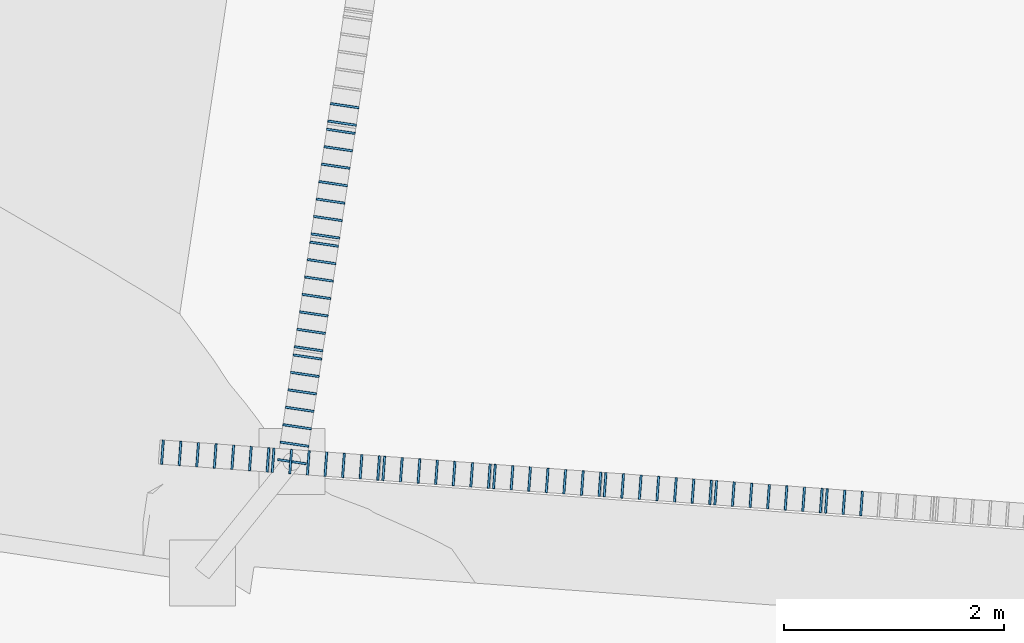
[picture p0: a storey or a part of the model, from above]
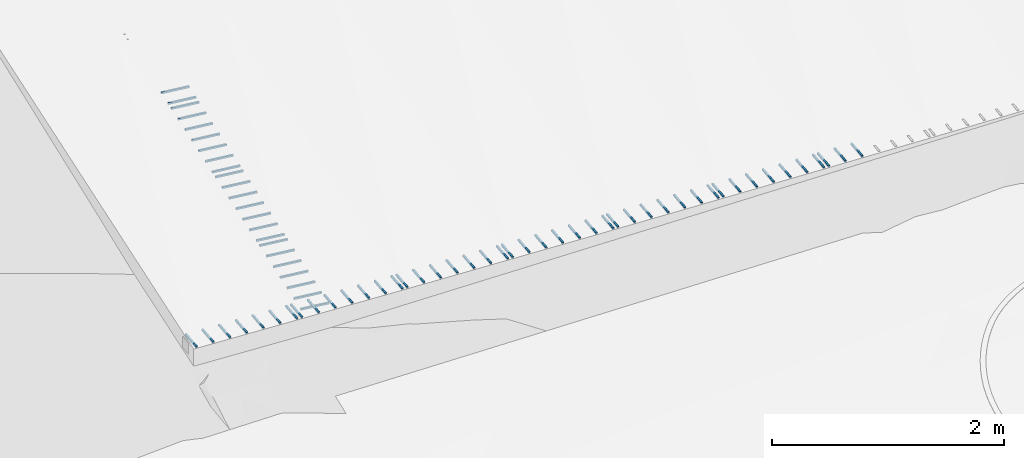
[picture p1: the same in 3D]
Properties of the parts of a building model (IFC4), part 1 of 4

# File
Description: ViewDefinition [CoordinationView]
File name: Casa_Sobreposta_Implantada.ifc
Time: 2026-10-02T14:30:32
Written by: IfcOpenShell 0.8.0
Made in: IfcOpenShell 0.8.0

# IfcProject, Casa / Lares · R08 · Estufa
Pset_CasaModel - Design: R08 / estufa / lower hybrid podium and ground-supported parking; ReferenceFile: 260617_CasaDFL_Estrutura_Terreno.ifc; ModelStatus: DESIGN_STUDY; North: Survey grid +Y; Ramp: No exterior pedestrian ramp or vehicular bridge; EngineeringStatus: Member sizes, foundations, connections, bracing and environmental performance not verified; GroundFFL_m: 14.65; AreaLimit_m2: 250; CountedGeometricArea_m2: 181.073; GreenhouseExcludedByUser: yes; UpperFinishedFloor_m: 17.89; BalconiesExcludedByClient: yes; CoveredGroundBalcony_m2: 56.7788; PlanningComplianceEstablished: no; AreaBasis: Client-confirmed 250 m2 allowance: parking, cistern, balconies and open greenhouse excluded; enclosed upper rooms and stair enclosures count. Any storage would count. Geometric study, no independent PDM verification.

# IfcSite, Lares · Rua das Mercês · artigo 4771
Pset_SurveySource - File: GN_09.26_213 Lares.dwg; SHA256: 0bca0a0751148bad1398f92d81b795428f94a57fea5e37dec0e125cea70402a1; Area_m2: 1636.5; BoundaryHandle: 31B; CoordinateReference: PT-TM06 / ETRS89; TerrainStatus: Proposed grading; original survey in separate IFC

# IfcBuilding, Casa Sobreposta
Pset_CasaFloorAssembly - UpperFFL_m: 3.24; JoistUnderside_m: 2.968; JoistDepth_m: 0.24; OSB_m: 0.02; Membrane_m: 0.002; ProtectiveFinish_m: 0.01; Basis: TJI240 + OSB20 from reference; greenhouse waterproofing/finish assumed; imposed loads unverified
Pset_CasaPlacement - GroundFloorSurveyLevel_m: 14.65; UpperFloor: yes; MoveEast_m: 3; MoveSouth_m: 0.5; RotationFromGridEast_deg: -8.5; BoundarySetbackRequired_m: 3; RuleBasis: User project constraint
Pset_CasaRevision08 - Variant: estufa; HybridPodium: yes; ParkingGroundSupported: yes; GroundFFL_m: 14.65; TerraceFFL_m: 14.61; VehicularBridgeLength_m: 0; AccessGabions: no; Cut_m3: 106.804; Fill_m3: 2.37597; EarthworkExclusions: Topsoil, foundation/service trenches, soil replacement, construction working space and bulking; CoveredGroundBalconyClassification: EXCLUDED_BY_CLIENT; WindCapacityVerified: no

# IfcBuildingStorey (3)
In: Casa Sobreposta
Name | Elevation (m)
00 · Habitação e estacionamento | 14.65
01 · Jardim de inverno | 17.89
-01 · Cisterna sob o terraço | 12.05

# IfcSpace (18)
Pset_CasaProvenance - DesignSource: Casa Sobreposta / configuration.json; ReferenceFile: 260617_CasaDFL_Estrutura_Terreno.ifc; ConstructionBasis: DESIGN_ASSUMPTION; Note: Functional zone from configurator; overlaps with partition footprints removed on ground floor. Not certified usable floor area.
Name | In | PredefinedType | NetFloorArea (m2)
Sala | 00 · Habitação e estacionamento | INTERNAL | 31.359
Cozinha | 00 · Habitação e estacionamento | INTERNAL | 9.94248
Banho | 00 · Habitação e estacionamento | INTERNAL | 7.19804
WC | 00 · Habitação e estacionamento | INTERNAL | 1.231
Serviço | 00 · Habitação e estacionamento | INTERNAL | 4.16058
Acesso IS | 00 · Habitação e estacionamento | INTERNAL | 3.99017
Quarto 1 | 00 · Habitação e estacionamento | INTERNAL | 13.1145
Quarto 2 | 00 · Habitação e estacionamento | INTERNAL | 13.1145
Quarto / escritório | 00 · Habitação e estacionamento | INTERNAL | 37.8909
Circulação | 00 · Habitação e estacionamento | INTERNAL | 18.1139
Estacionamento · 2 lugares | 00 · Habitação e estacionamento | EXTERNAL | 32.55
Galeria sul · balanço 1,50 m | 01 · Jardim de inverno | INTERNAL | 48
Jardim de inverno | 01 · Jardim de inverno | INTERNAL | 47.852
Circulação / estar | 01 · Jardim de inverno | INTERNAL | 68.8278
Banho superior | 01 · Jardim de inverno | INTERNAL | 7.3678
Cultivo / jardim | 01 · Jardim de inverno | INTERNAL | 25.5734
Estar sobre a garagem | 01 · Jardim de inverno | INTERNAL | 21.292
Balanço | 01 · Jardim de inverno | INTERNAL | 25.6

# IfcAnnotation (4)
Pset_CasaProvenance - DesignSource: Casa Sobreposta / configuration.json; ReferenceFile: 260617_CasaDFL_Estrutura_Terreno.ifc; ConstructionBasis: DESIGN_ASSUMPTION
Name | In
Lugar P1 · 2.50 x 5.00 m | 00 · Habitação e estacionamento
Lugar P2 · 2.50 x 5.00 m | 00 · Habitação e estacionamento
Limite levantado · 31B | Lares · Rua das Mercês · artigo 4771
Afastamento de implantação · 3 m | Lares · Rua das Mercês · artigo 4771

# IfcBeam (115)
Pset_CasaProvenance - DesignSource: Casa Sobreposta / configuration.json; ReferenceFile: 260617_CasaDFL_Estrutura_Terreno.ifc
Name | In | Material | ConstructionBasis | Note
TJI240 · 0.065 / -1.15 | 01 · Jardim de inverno | Madeira / Bauholz (2), OSB | ADAPTED_REFERENCE | Composite wood flanges + OSB web; 600 mm study spacing. Reference 44.45 mm width / 9.525 mm web; flanges regularised to 28 mm. Not structurally sized.
TJI240 · 4.065 / -1.15 | 01 · Jardim de inverno | Madeira / Bauholz (2), OSB | ADAPTED_REFERENCE | Composite wood flanges + OSB web; 600 mm study spacing. Reference 44.45 mm width / 9.525 mm web; flanges regularised to 28 mm. Not structurally sized.
TJI240 · 8.065 / -1.15 | 01 · Jardim de inverno | Madeira / Bauholz (2), OSB | ADAPTED_REFERENCE | Composite wood flanges + OSB web; 600 mm study spacing. Reference 44.45 mm width / 9.525 mm web; flanges regularised to 28 mm. Not structurally sized.
TJI240 · 12.065 / -1.15 | 01 · Jardim de inverno | Madeira / Bauholz (2), OSB | ADAPTED_REFERENCE | Composite wood flanges + OSB web; 600 mm study spacing. Reference 44.45 mm width / 9.525 mm web; flanges regularised to 28 mm. Not structurally sized.
TJI240 · 16.065 / -1.15 | 01 · Jardim de inverno | Madeira / Bauholz (2), OSB | ADAPTED_REFERENCE | Composite wood flanges + OSB web; 600 mm study spacing. Reference 44.45 mm width / 9.525 mm web; flanges regularised to 28 mm. Not structurally sized.
TJI240 · 20.065 / -1.15 | 01 · Jardim de inverno | Madeira / Bauholz (2), OSB | ADAPTED_REFERENCE | Composite wood flanges + OSB web; 600 mm study spacing. Reference 44.45 mm width / 9.525 mm web; flanges regularised to 28 mm. Not structurally sized.
TJI240 · 24.065 / -1.15 | 01 · Jardim de inverno | Madeira / Bauholz (2), OSB | ADAPTED_REFERENCE | Composite wood flanges + OSB web; 600 mm study spacing. Reference 44.45 mm width / 9.525 mm web; flanges regularised to 28 mm. Not structurally sized.
TJI240 · 28.065 / -1.15 | 01 · Jardim de inverno | Madeira / Bauholz (2), OSB | ADAPTED_REFERENCE | Composite wood flanges + OSB web; 600 mm study spacing. Reference 44.45 mm width / 9.525 mm web; flanges regularised to 28 mm. Not structurally sized.
TJI240 · 0.065 / -0.55 | 01 · Jardim de inverno | Madeira / Bauholz (2), OSB | ADAPTED_REFERENCE | Composite wood flanges + OSB web; 600 mm study spacing. Reference 44.45 mm width / 9.525 mm web; flanges regularised to 28 mm. Not structurally sized.
TJI240 · 4.065 / -0.55 | 01 · Jardim de inverno | Madeira / Bauholz (2), OSB | ADAPTED_REFERENCE | Composite wood flanges + OSB web; 600 mm study spacing. Reference 44.45 mm width / 9.525 mm web; flanges regularised to 28 mm. Not structurally sized.
TJI240 · 8.065 / -0.55 | 01 · Jardim de inverno | Madeira / Bauholz (2), OSB | ADAPTED_REFERENCE | Composite wood flanges + OSB web; 600 mm study spacing. Reference 44.45 mm width / 9.525 mm web; flanges regularised to 28 mm. Not structurally sized.
TJI240 · 12.065 / -0.55 | 01 · Jardim de inverno | Madeira / Bauholz (2), OSB | ADAPTED_REFERENCE | Composite wood flanges + OSB web; 600 mm study spacing. Reference 44.45 mm width / 9.525 mm web; flanges regularised to 28 mm. Not structurally sized.
TJI240 · 16.065 / -0.55 | 01 · Jardim de inverno | Madeira / Bauholz (2), OSB | ADAPTED_REFERENCE | Composite wood flanges + OSB web; 600 mm study spacing. Reference 44.45 mm width / 9.525 mm web; flanges regularised to 28 mm. Not structurally sized.
TJI240 · 20.065 / -0.55 | 01 · Jardim de inverno | Madeira / Bauholz (2), OSB | ADAPTED_REFERENCE | Composite wood flanges + OSB web; 600 mm study spacing. Reference 44.45 mm width / 9.525 mm web; flanges regularised to 28 mm. Not structurally sized.
TJI240 · 24.065 / -0.55 | 01 · Jardim de inverno | Madeira / Bauholz (2), OSB | ADAPTED_REFERENCE | Composite wood flanges + OSB web; 600 mm study spacing. Reference 44.45 mm width / 9.525 mm web; flanges regularised to 28 mm. Not structurally sized.
TJI240 · 28.065 / -0.55 | 01 · Jardim de inverno | Madeira / Bauholz (2), OSB | ADAPTED_REFERENCE | Composite wood flanges + OSB web; 600 mm study spacing. Reference 44.45 mm width / 9.525 mm web; flanges regularised to 28 mm. Not structurally sized.
TJI240 · 0.065 / 0.05 | 01 · Jardim de inverno | Madeira / Bauholz (2), OSB | ADAPTED_REFERENCE | Composite wood flanges + OSB web; 600 mm study spacing. Reference 44.45 mm width / 9.525 mm web; flanges regularised to 28 mm. Not structurally sized.
TJI240 · 4.065 / 0.05 | 01 · Jardim de inverno | Madeira / Bauholz (2), OSB | ADAPTED_REFERENCE | Composite wood flanges + OSB web; 600 mm study spacing. Reference 44.45 mm width / 9.525 mm web; flanges regularised to 28 mm. Not structurally sized.
TJI240 · 8.065 / 0.05 | 01 · Jardim de inverno | Madeira / Bauholz (2), OSB | ADAPTED_REFERENCE | Composite wood flanges + OSB web; 600 mm study spacing. Reference 44.45 mm width / 9.525 mm web; flanges regularised to 28 mm. Not structurally sized.
TJI240 · 12.065 / 0.05 | 01 · Jardim de inverno | Madeira / Bauholz (2), OSB | ADAPTED_REFERENCE | Composite wood flanges + OSB web; 600 mm study spacing. Reference 44.45 mm width / 9.525 mm web; flanges regularised to 28 mm. Not structurally sized.
TJI240 · 16.065 / 0.05 | 01 · Jardim de inverno | Madeira / Bauholz (2), OSB | ADAPTED_REFERENCE | Composite wood flanges + OSB web; 600 mm study spacing. Reference 44.45 mm width / 9.525 mm web; flanges regularised to 28 mm. Not structurally sized.
TJI240 · 20.065 / 0.05 | 01 · Jardim de inverno | Madeira / Bauholz (2), OSB | ADAPTED_REFERENCE | Composite wood flanges + OSB web; 600 mm study spacing. Reference 44.45 mm width / 9.525 mm web; flanges regularised to 28 mm. Not structurally sized.
TJI240 · 24.065 / 0.05 | 01 · Jardim de inverno | Madeira / Bauholz (2), OSB | ADAPTED_REFERENCE | Composite wood flanges + OSB web; 600 mm study spacing. Reference 44.45 mm width / 9.525 mm web; flanges regularised to 28 mm. Not structurally sized.
TJI240 · 28.065 / 0.05 | 01 · Jardim de inverno | Madeira / Bauholz (2), OSB | ADAPTED_REFERENCE | Composite wood flanges + OSB web; 600 mm study spacing. Reference 44.45 mm width / 9.525 mm web; flanges regularised to 28 mm. Not structurally sized.
TJI240 · 0.065 / 0.65 | 01 · Jardim de inverno | Madeira / Bauholz (2), OSB | ADAPTED_REFERENCE | Composite wood flanges + OSB web; 600 mm study spacing. Reference 44.45 mm width / 9.525 mm web; flanges regularised to 28 mm. Not structurally sized.
TJI240 · 4.065 / 0.65 | 01 · Jardim de inverno | Madeira / Bauholz (2), OSB | ADAPTED_REFERENCE | Composite wood flanges + OSB web; 600 mm study spacing. Reference 44.45 mm width / 9.525 mm web; flanges regularised to 28 mm. Not structurally sized.
TJI240 · 8.065 / 0.65 | 01 · Jardim de inverno | Madeira / Bauholz (2), OSB | ADAPTED_REFERENCE | Composite wood flanges + OSB web; 600 mm study spacing. Reference 44.45 mm width / 9.525 mm web; flanges regularised to 28 mm. Not structurally sized.
TJI240 · 12.065 / 0.65 | 01 · Jardim de inverno | Madeira / Bauholz (2), OSB | ADAPTED_REFERENCE | Composite wood flanges + OSB web; 600 mm study spacing. Reference 44.45 mm width / 9.525 mm web; flanges regularised to 28 mm. Not structurally sized.
TJI240 · 16.065 / 0.65 | 01 · Jardim de inverno | Madeira / Bauholz (2), OSB | ADAPTED_REFERENCE | Composite wood flanges + OSB web; 600 mm study spacing. Reference 44.45 mm width / 9.525 mm web; flanges regularised to 28 mm. Not structurally sized.
TJI240 · 20.065 / 0.65 | 01 · Jardim de inverno | Madeira / Bauholz (2), OSB | ADAPTED_REFERENCE | Composite wood flanges + OSB web; 600 mm study spacing. Reference 44.45 mm width / 9.525 mm web; flanges regularised to 28 mm. Not structurally sized.
TJI240 · 24.065 / 0.65 | 01 · Jardim de inverno | Madeira / Bauholz (2), OSB | ADAPTED_REFERENCE | Composite wood flanges + OSB web; 600 mm study spacing. Reference 44.45 mm width / 9.525 mm web; flanges regularised to 28 mm. Not structurally sized.
TJI240 · 28.065 / 0.65 | 01 · Jardim de inverno | Madeira / Bauholz (2), OSB | ADAPTED_REFERENCE | Composite wood flanges + OSB web; 600 mm study spacing. Reference 44.45 mm width / 9.525 mm web; flanges regularised to 28 mm. Not structurally sized.
TJI240 · 0.970 / 1.25 | 01 · Jardim de inverno | Madeira / Bauholz (2), OSB | ADAPTED_REFERENCE | Composite wood flanges + OSB web; 600 mm study spacing. Reference 44.45 mm width / 9.525 mm web; flanges regularised to 28 mm. Not structurally sized.
TJI240 · 4.065 / 1.25 | 01 · Jardim de inverno | Madeira / Bauholz (2), OSB | ADAPTED_REFERENCE | Composite wood flanges + OSB web; 600 mm study spacing. Reference 44.45 mm width / 9.525 mm web; flanges regularised to 28 mm. Not structurally sized.
TJI240 · 8.065 / 1.25 | 01 · Jardim de inverno | Madeira / Bauholz (2), OSB | ADAPTED_REFERENCE | Composite wood flanges + OSB web; 600 mm study spacing. Reference 44.45 mm width / 9.525 mm web; flanges regularised to 28 mm. Not structurally sized.
TJI240 · 12.065 / 1.25 | 01 · Jardim de inverno | Madeira / Bauholz (2), OSB | ADAPTED_REFERENCE | Composite wood flanges + OSB web; 600 mm study spacing. Reference 44.45 mm width / 9.525 mm web; flanges regularised to 28 mm. Not structurally sized.
TJI240 · 16.065 / 1.25 | 01 · Jardim de inverno | Madeira / Bauholz (2), OSB | ADAPTED_REFERENCE | Composite wood flanges + OSB web; 600 mm study spacing. Reference 44.45 mm width / 9.525 mm web; flanges regularised to 28 mm. Not structurally sized.
TJI240 · 20.065 / 1.25 | 01 · Jardim de inverno | Madeira / Bauholz (2), OSB | ADAPTED_REFERENCE | Composite wood flanges + OSB web; 600 mm study spacing. Reference 44.45 mm width / 9.525 mm web; flanges regularised to 28 mm. Not structurally sized.
TJI240 · 25.040 / 1.25 | 01 · Jardim de inverno | Madeira / Bauholz (2), OSB | ADAPTED_REFERENCE | Composite wood flanges + OSB web; 600 mm study spacing. Reference 44.45 mm width / 9.525 mm web; flanges regularised to 28 mm. Not structurally sized.
TJI240 · 28.065 / 1.25 | 01 · Jardim de inverno | Madeira / Bauholz (2), OSB | ADAPTED_REFERENCE | Composite wood flanges + OSB web; 600 mm study spacing. Reference 44.45 mm width / 9.525 mm web; flanges regularised to 28 mm. Not structurally sized.
TJI240 · 0.970 / 1.85 | 01 · Jardim de inverno | Madeira / Bauholz (2), OSB | ADAPTED_REFERENCE | Composite wood flanges + OSB web; 600 mm study spacing. Reference 44.45 mm width / 9.525 mm web; flanges regularised to 28 mm. Not structurally sized.
TJI240 · 4.065 / 1.85 | 01 · Jardim de inverno | Madeira / Bauholz (2), OSB | ADAPTED_REFERENCE | Composite wood flanges + OSB web; 600 mm study spacing. Reference 44.45 mm width / 9.525 mm web; flanges regularised to 28 mm. Not structurally sized.
TJI240 · 8.065 / 1.85 | 01 · Jardim de inverno | Madeira / Bauholz (2), OSB | ADAPTED_REFERENCE | Composite wood flanges + OSB web; 600 mm study spacing. Reference 44.45 mm width / 9.525 mm web; flanges regularised to 28 mm. Not structurally sized.
TJI240 · 12.065 / 1.85 | 01 · Jardim de inverno | Madeira / Bauholz (2), OSB | ADAPTED_REFERENCE | Composite wood flanges + OSB web; 600 mm study spacing. Reference 44.45 mm width / 9.525 mm web; flanges regularised to 28 mm. Not structurally sized.
TJI240 · 16.065 / 1.85 | 01 · Jardim de inverno | Madeira / Bauholz (2), OSB | ADAPTED_REFERENCE | Composite wood flanges + OSB web; 600 mm study spacing. Reference 44.45 mm width / 9.525 mm web; flanges regularised to 28 mm. Not structurally sized.
TJI240 · 20.065 / 1.85 | 01 · Jardim de inverno | Madeira / Bauholz (2), OSB | ADAPTED_REFERENCE | Composite wood flanges + OSB web; 600 mm study spacing. Reference 44.45 mm width / 9.525 mm web; flanges regularised to 28 mm. Not structurally sized.
TJI240 · 25.040 / 1.85 | 01 · Jardim de inverno | Madeira / Bauholz (2), OSB | ADAPTED_REFERENCE | Composite wood flanges + OSB web; 600 mm study spacing. Reference 44.45 mm width / 9.525 mm web; flanges regularised to 28 mm. Not structurally sized.
TJI240 · 28.065 / 1.85 | 01 · Jardim de inverno | Madeira / Bauholz (2), OSB | ADAPTED_REFERENCE | Composite wood flanges + OSB web; 600 mm study spacing. Reference 44.45 mm width / 9.525 mm web; flanges regularised to 28 mm. Not structurally sized.
TJI240 · 0.970 / 2.45 | 01 · Jardim de inverno | Madeira / Bauholz (2), OSB | ADAPTED_REFERENCE | Composite wood flanges + OSB web; 600 mm study spacing. Reference 44.45 mm width / 9.525 mm web; flanges regularised to 28 mm. Not structurally sized.
TJI240 · 4.065 / 2.45 | 01 · Jardim de inverno | Madeira / Bauholz (2), OSB | ADAPTED_REFERENCE | Composite wood flanges + OSB web; 600 mm study spacing. Reference 44.45 mm width / 9.525 mm web; flanges regularised to 28 mm. Not structurally sized.
TJI240 · 8.065 / 2.45 | 01 · Jardim de inverno | Madeira / Bauholz (2), OSB | ADAPTED_REFERENCE | Composite wood flanges + OSB web; 600 mm study spacing. Reference 44.45 mm width / 9.525 mm web; flanges regularised to 28 mm. Not structurally sized.
TJI240 · 12.065 / 2.45 | 01 · Jardim de inverno | Madeira / Bauholz (2), OSB | ADAPTED_REFERENCE | Composite wood flanges + OSB web; 600 mm study spacing. Reference 44.45 mm width / 9.525 mm web; flanges regularised to 28 mm. Not structurally sized.
TJI240 · 16.065 / 2.45 | 01 · Jardim de inverno | Madeira / Bauholz (2), OSB | ADAPTED_REFERENCE | Composite wood flanges + OSB web; 600 mm study spacing. Reference 44.45 mm width / 9.525 mm web; flanges regularised to 28 mm. Not structurally sized.
TJI240 · 20.065 / 2.45 | 01 · Jardim de inverno | Madeira / Bauholz (2), OSB | ADAPTED_REFERENCE | Composite wood flanges + OSB web; 600 mm study spacing. Reference 44.45 mm width / 9.525 mm web; flanges regularised to 28 mm. Not structurally sized.
TJI240 · 25.040 / 2.45 | 01 · Jardim de inverno | Madeira / Bauholz (2), OSB | ADAPTED_REFERENCE | Composite wood flanges + OSB web; 600 mm study spacing. Reference 44.45 mm width / 9.525 mm web; flanges regularised to 28 mm. Not structurally sized.
TJI240 · 28.065 / 2.45 | 01 · Jardim de inverno | Madeira / Bauholz (2), OSB | ADAPTED_REFERENCE | Composite wood flanges + OSB web; 600 mm study spacing. Reference 44.45 mm width / 9.525 mm web; flanges regularised to 28 mm. Not structurally sized.
TJI240 · 0.970 / 3.05 | 01 · Jardim de inverno | Madeira / Bauholz (2), OSB | ADAPTED_REFERENCE | Composite wood flanges + OSB web; 600 mm study spacing. Reference 44.45 mm width / 9.525 mm web; flanges regularised to 28 mm. Not structurally sized.
TJI240 · 4.065 / 3.05 | 01 · Jardim de inverno | Madeira / Bauholz (2), OSB | ADAPTED_REFERENCE | Composite wood flanges + OSB web; 600 mm study spacing. Reference 44.45 mm width / 9.525 mm web; flanges regularised to 28 mm. Not structurally sized.
TJI240 · 8.065 / 3.05 | 01 · Jardim de inverno | Madeira / Bauholz (2), OSB | ADAPTED_REFERENCE | Composite wood flanges + OSB web; 600 mm study spacing. Reference 44.45 mm width / 9.525 mm web; flanges regularised to 28 mm. Not structurally sized.
TJI240 · 12.065 / 3.05 | 01 · Jardim de inverno | Madeira / Bauholz (2), OSB | ADAPTED_REFERENCE | Composite wood flanges + OSB web; 600 mm study spacing. Reference 44.45 mm width / 9.525 mm web; flanges regularised to 28 mm. Not structurally sized.
TJI240 · 16.065 / 3.05 | 01 · Jardim de inverno | Madeira / Bauholz (2), OSB | ADAPTED_REFERENCE | Composite wood flanges + OSB web; 600 mm study spacing. Reference 44.45 mm width / 9.525 mm web; flanges regularised to 28 mm. Not structurally sized.
TJI240 · 20.065 / 3.05 | 01 · Jardim de inverno | Madeira / Bauholz (2), OSB | ADAPTED_REFERENCE | Composite wood flanges + OSB web; 600 mm study spacing. Reference 44.45 mm width / 9.525 mm web; flanges regularised to 28 mm. Not structurally sized.
TJI240 · 25.040 / 3.05 | 01 · Jardim de inverno | Madeira / Bauholz (2), OSB | ADAPTED_REFERENCE | Composite wood flanges + OSB web; 600 mm study spacing. Reference 44.45 mm width / 9.525 mm web; flanges regularised to 28 mm. Not structurally sized.
TJI240 · 28.065 / 3.05 | 01 · Jardim de inverno | Madeira / Bauholz (2), OSB | ADAPTED_REFERENCE | Composite wood flanges + OSB web; 600 mm study spacing. Reference 44.45 mm width / 9.525 mm web; flanges regularised to 28 mm. Not structurally sized.
TJI240 · 0.970 / 3.65 | 01 · Jardim de inverno | Madeira / Bauholz (2), OSB | ADAPTED_REFERENCE | Composite wood flanges + OSB web; 600 mm study spacing. Reference 44.45 mm width / 9.525 mm web; flanges regularised to 28 mm. Not structurally sized.
TJI240 · 4.065 / 3.65 | 01 · Jardim de inverno | Madeira / Bauholz (2), OSB | ADAPTED_REFERENCE | Composite wood flanges + OSB web; 600 mm study spacing. Reference 44.45 mm width / 9.525 mm web; flanges regularised to 28 mm. Not structurally sized.
TJI240 · 8.065 / 3.65 | 01 · Jardim de inverno | Madeira / Bauholz (2), OSB | ADAPTED_REFERENCE | Composite wood flanges + OSB web; 600 mm study spacing. Reference 44.45 mm width / 9.525 mm web; flanges regularised to 28 mm. Not structurally sized.
TJI240 · 12.065 / 3.65 | 01 · Jardim de inverno | Madeira / Bauholz (2), OSB | ADAPTED_REFERENCE | Composite wood flanges + OSB web; 600 mm study spacing. Reference 44.45 mm width / 9.525 mm web; flanges regularised to 28 mm. Not structurally sized.
TJI240 · 16.065 / 3.65 | 01 · Jardim de inverno | Madeira / Bauholz (2), OSB | ADAPTED_REFERENCE | Composite wood flanges + OSB web; 600 mm study spacing. Reference 44.45 mm width / 9.525 mm web; flanges regularised to 28 mm. Not structurally sized.
TJI240 · 20.065 / 3.65 | 01 · Jardim de inverno | Madeira / Bauholz (2), OSB | ADAPTED_REFERENCE | Composite wood flanges + OSB web; 600 mm study spacing. Reference 44.45 mm width / 9.525 mm web; flanges regularised to 28 mm. Not structurally sized.
TJI240 · 25.040 / 3.65 | 01 · Jardim de inverno | Madeira / Bauholz (2), OSB | ADAPTED_REFERENCE | Composite wood flanges + OSB web; 600 mm study spacing. Reference 44.45 mm width / 9.525 mm web; flanges regularised to 28 mm. Not structurally sized.
TJI240 · 28.065 / 3.65 | 01 · Jardim de inverno | Madeira / Bauholz (2), OSB | ADAPTED_REFERENCE | Composite wood flanges + OSB web; 600 mm study spacing. Reference 44.45 mm width / 9.525 mm web; flanges regularised to 28 mm. Not structurally sized.
TJI240 · 0.970 / 4.25 | 01 · Jardim de inverno | Madeira / Bauholz (2), OSB | ADAPTED_REFERENCE | Composite wood flanges + OSB web; 600 mm study spacing. Reference 44.45 mm width / 9.525 mm web; flanges regularised to 28 mm. Not structurally sized.
TJI240 · 4.065 / 4.25 | 01 · Jardim de inverno | Madeira / Bauholz (2), OSB | ADAPTED_REFERENCE | Composite wood flanges + OSB web; 600 mm study spacing. Reference 44.45 mm width / 9.525 mm web; flanges regularised to 28 mm. Not structurally sized.
TJI240 · 8.065 / 4.25 | 01 · Jardim de inverno | Madeira / Bauholz (2), OSB | ADAPTED_REFERENCE | Composite wood flanges + OSB web; 600 mm study spacing. Reference 44.45 mm width / 9.525 mm web; flanges regularised to 28 mm. Not structurally sized.
TJI240 · 12.065 / 4.25 | 01 · Jardim de inverno | Madeira / Bauholz (2), OSB | ADAPTED_REFERENCE | Composite wood flanges + OSB web; 600 mm study spacing. Reference 44.45 mm width / 9.525 mm web; flanges regularised to 28 mm. Not structurally sized.
TJI240 · 16.065 / 4.25 | 01 · Jardim de inverno | Madeira / Bauholz (2), OSB | ADAPTED_REFERENCE | Composite wood flanges + OSB web; 600 mm study spacing. Reference 44.45 mm width / 9.525 mm web; flanges regularised to 28 mm. Not structurally sized.
TJI240 · 20.065 / 4.25 | 01 · Jardim de inverno | Madeira / Bauholz (2), OSB | ADAPTED_REFERENCE | Composite wood flanges + OSB web; 600 mm study spacing. Reference 44.45 mm width / 9.525 mm web; flanges regularised to 28 mm. Not structurally sized.
TJI240 · 25.040 / 4.25 | 01 · Jardim de inverno | Madeira / Bauholz (2), OSB | ADAPTED_REFERENCE | Composite wood flanges + OSB web; 600 mm study spacing. Reference 44.45 mm width / 9.525 mm web; flanges regularised to 28 mm. Not structurally sized.
TJI240 · 28.065 / 4.25 | 01 · Jardim de inverno | Madeira / Bauholz (2), OSB | ADAPTED_REFERENCE | Composite wood flanges + OSB web; 600 mm study spacing. Reference 44.45 mm width / 9.525 mm web; flanges regularised to 28 mm. Not structurally sized.
TJI240 · 0.970 / 4.85 | 01 · Jardim de inverno | Madeira / Bauholz (2), OSB | ADAPTED_REFERENCE | Composite wood flanges + OSB web; 600 mm study spacing. Reference 44.45 mm width / 9.525 mm web; flanges regularised to 28 mm. Not structurally sized.
TJI240 · 4.065 / 4.85 | 01 · Jardim de inverno | Madeira / Bauholz (2), OSB | ADAPTED_REFERENCE | Composite wood flanges + OSB web; 600 mm study spacing. Reference 44.45 mm width / 9.525 mm web; flanges regularised to 28 mm. Not structurally sized.
TJI240 · 8.065 / 4.85 | 01 · Jardim de inverno | Madeira / Bauholz (2), OSB | ADAPTED_REFERENCE | Composite wood flanges + OSB web; 600 mm study spacing. Reference 44.45 mm width / 9.525 mm web; flanges regularised to 28 mm. Not structurally sized.
TJI240 · 12.065 / 4.85 | 01 · Jardim de inverno | Madeira / Bauholz (2), OSB | ADAPTED_REFERENCE | Composite wood flanges + OSB web; 600 mm study spacing. Reference 44.45 mm width / 9.525 mm web; flanges regularised to 28 mm. Not structurally sized.
TJI240 · 16.065 / 4.85 | 01 · Jardim de inverno | Madeira / Bauholz (2), OSB | ADAPTED_REFERENCE | Composite wood flanges + OSB web; 600 mm study spacing. Reference 44.45 mm width / 9.525 mm web; flanges regularised to 28 mm. Not structurally sized.
TJI240 · 20.065 / 4.85 | 01 · Jardim de inverno | Madeira / Bauholz (2), OSB | ADAPTED_REFERENCE | Composite wood flanges + OSB web; 600 mm study spacing. Reference 44.45 mm width / 9.525 mm web; flanges regularised to 28 mm. Not structurally sized.
TJI240 · 25.040 / 4.85 | 01 · Jardim de inverno | Madeira / Bauholz (2), OSB | ADAPTED_REFERENCE | Composite wood flanges + OSB web; 600 mm study spacing. Reference 44.45 mm width / 9.525 mm web; flanges regularised to 28 mm. Not structurally sized.
TJI240 · 28.065 / 4.85 | 01 · Jardim de inverno | Madeira / Bauholz (2), OSB | ADAPTED_REFERENCE | Composite wood flanges + OSB web; 600 mm study spacing. Reference 44.45 mm width / 9.525 mm web; flanges regularised to 28 mm. Not structurally sized.
TJI240 · 0.970 / 5.45 | 01 · Jardim de inverno | Madeira / Bauholz (2), OSB | ADAPTED_REFERENCE | Composite wood flanges + OSB web; 600 mm study spacing. Reference 44.45 mm width / 9.525 mm web; flanges regularised to 28 mm. Not structurally sized.
TJI240 · 4.065 / 5.45 | 01 · Jardim de inverno | Madeira / Bauholz (2), OSB | ADAPTED_REFERENCE | Composite wood flanges + OSB web; 600 mm study spacing. Reference 44.45 mm width / 9.525 mm web; flanges regularised to 28 mm. Not structurally sized.
TJI240 · 8.065 / 5.45 | 01 · Jardim de inverno | Madeira / Bauholz (2), OSB | ADAPTED_REFERENCE | Composite wood flanges + OSB web; 600 mm study spacing. Reference 44.45 mm width / 9.525 mm web; flanges regularised to 28 mm. Not structurally sized.
TJI240 · 12.065 / 5.45 | 01 · Jardim de inverno | Madeira / Bauholz (2), OSB | ADAPTED_REFERENCE | Composite wood flanges + OSB web; 600 mm study spacing. Reference 44.45 mm width / 9.525 mm web; flanges regularised to 28 mm. Not structurally sized.
TJI240 · 16.065 / 5.45 | 01 · Jardim de inverno | Madeira / Bauholz (2), OSB | ADAPTED_REFERENCE | Composite wood flanges + OSB web; 600 mm study spacing. Reference 44.45 mm width / 9.525 mm web; flanges regularised to 28 mm. Not structurally sized.
TJI240 · 20.065 / 5.45 | 01 · Jardim de inverno | Madeira / Bauholz (2), OSB | ADAPTED_REFERENCE | Composite wood flanges + OSB web; 600 mm study spacing. Reference 44.45 mm width / 9.525 mm web; flanges regularised to 28 mm. Not structurally sized.
TJI240 · 25.040 / 5.45 | 01 · Jardim de inverno | Madeira / Bauholz (2), OSB | ADAPTED_REFERENCE | Composite wood flanges + OSB web; 600 mm study spacing. Reference 44.45 mm width / 9.525 mm web; flanges regularised to 28 mm. Not structurally sized.
TJI240 · 28.065 / 5.45 | 01 · Jardim de inverno | Madeira / Bauholz (2), OSB | ADAPTED_REFERENCE | Composite wood flanges + OSB web; 600 mm study spacing. Reference 44.45 mm width / 9.525 mm web; flanges regularised to 28 mm. Not structurally sized.
TJI240 · 0.065 / 6.05 | 01 · Jardim de inverno | Madeira / Bauholz (2), OSB | ADAPTED_REFERENCE | Composite wood flanges + OSB web; 600 mm study spacing. Reference 44.45 mm width / 9.525 mm web; flanges regularised to 28 mm. Not structurally sized.
TJI240 · 4.065 / 6.05 | 01 · Jardim de inverno | Madeira / Bauholz (2), OSB | ADAPTED_REFERENCE | Composite wood flanges + OSB web; 600 mm study spacing. Reference 44.45 mm width / 9.525 mm web; flanges regularised to 28 mm. Not structurally sized.
TJI240 · 8.065 / 6.05 | 01 · Jardim de inverno | Madeira / Bauholz (2), OSB | ADAPTED_REFERENCE | Composite wood flanges + OSB web; 600 mm study spacing. Reference 44.45 mm width / 9.525 mm web; flanges regularised to 28 mm. Not structurally sized.
TJI240 · 12.065 / 6.05 | 01 · Jardim de inverno | Madeira / Bauholz (2), OSB | ADAPTED_REFERENCE | Composite wood flanges + OSB web; 600 mm study spacing. Reference 44.45 mm width / 9.525 mm web; flanges regularised to 28 mm. Not structurally sized.
TJI240 · 16.065 / 6.05 | 01 · Jardim de inverno | Madeira / Bauholz (2), OSB | ADAPTED_REFERENCE | Composite wood flanges + OSB web; 600 mm study spacing. Reference 44.45 mm width / 9.525 mm web; flanges regularised to 28 mm. Not structurally sized.
TJI240 · 20.065 / 6.05 | 01 · Jardim de inverno | Madeira / Bauholz (2), OSB | ADAPTED_REFERENCE | Composite wood flanges + OSB web; 600 mm study spacing. Reference 44.45 mm width / 9.525 mm web; flanges regularised to 28 mm. Not structurally sized.
TJI240 · 24.065 / 6.05 | 01 · Jardim de inverno | Madeira / Bauholz (2), OSB | ADAPTED_REFERENCE | Composite wood flanges + OSB web; 600 mm study spacing. Reference 44.45 mm width / 9.525 mm web; flanges regularised to 28 mm. Not structurally sized.
TJI240 · 28.065 / 6.05 | 01 · Jardim de inverno | Madeira / Bauholz (2), OSB | ADAPTED_REFERENCE | Composite wood flanges + OSB web; 600 mm study spacing. Reference 44.45 mm width / 9.525 mm web; flanges regularised to 28 mm. Not structurally sized.
8 x Pódio suspenso · viga transversal | 00 · Habitação e estacionamento | Betão armado / Stahlbeton | DESIGN_ASSUMPTION
3 x Pódio suspenso · viga longitudinal | 00 · Habitação e estacionamento | Betão armado / Stahlbeton | DESIGN_ASSUMPTION

# IfcBeam: IPE240 / steel (46)
Type - Material: Aço pintado / Stahl lackiert
Pset_CasaProvenance - DesignSource: Casa Sobreposta / configuration.json; ReferenceFile: 260617_CasaDFL_Estrutura_Terreno.ifc; ConstructionBasis: ADAPTED_REFERENCE; Note: Reference section; spans, stability and connections require design.
Name | In
Viga longitudinal 0 / 0.12 | 01 · Jardim de inverno
Viga longitudinal 4 / 0.12 | 01 · Jardim de inverno
Viga longitudinal 8 / 0.12 | 01 · Jardim de inverno
Viga longitudinal 12 / 0.12 | 01 · Jardim de inverno
Viga longitudinal 16 / 0.12 | 01 · Jardim de inverno
Viga longitudinal 20 / 0.12 | 01 · Jardim de inverno
Viga longitudinal 24 / 0.12 | 01 · Jardim de inverno
Viga longitudinal 28 / 0.12 | 01 · Jardim de inverno
Viga longitudinal 0 / 6.28 | 01 · Jardim de inverno
Viga longitudinal 4 / 6.28 | 01 · Jardim de inverno
Viga longitudinal 8 / 6.28 | 01 · Jardim de inverno
Viga longitudinal 12 / 6.28 | 01 · Jardim de inverno
Viga longitudinal 16 / 6.28 | 01 · Jardim de inverno
Viga longitudinal 20 / 6.28 | 01 · Jardim de inverno
Viga longitudinal 24 / 6.28 | 01 · Jardim de inverno
Viga longitudinal 28 / 6.28 | 01 · Jardim de inverno
Viga longitudinal 0 / -1.44 | 01 · Jardim de inverno
Viga longitudinal 4 / -1.44 | 01 · Jardim de inverno
Viga longitudinal 8 / -1.44 | 01 · Jardim de inverno
Viga longitudinal 12 / -1.44 | 01 · Jardim de inverno
Viga longitudinal 16 / -1.44 | 01 · Jardim de inverno
Viga longitudinal 20 / -1.44 | 01 · Jardim de inverno
Viga longitudinal 24 / -1.44 | 01 · Jardim de inverno
Viga longitudinal 28 / -1.44 | 01 · Jardim de inverno
2 x Viga transversal eixo 0 | 01 · Jardim de inverno
Viga transversal eixo 4 | 01 · Jardim de inverno
Viga transversal eixo 8 | 01 · Jardim de inverno
Viga transversal eixo 12 | 01 · Jardim de inverno
Viga transversal eixo 16 | 01 · Jardim de inverno
Viga transversal eixo 20 | 01 · Jardim de inverno
Viga transversal eixo 24 | 01 · Jardim de inverno
Viga transversal eixo 28 | 01 · Jardim de inverno
Viga transversal eixo 32 | 01 · Jardim de inverno
2 x Longarina do vão 1 | 01 · Jardim de inverno
2 x Cabeceira do vão 1 | 01 · Jardim de inverno
2 x Longarina do vão 2 | 01 · Jardim de inverno
2 x Cabeceira do vão 2 | 01 · Jardim de inverno
2 x Varanda · viga de bordo | 00 · Habitação e estacionamento
2 x Varanda · viga transversal | 00 · Habitação e estacionamento

# IfcBeam: RHS100x60x4 / steel (4)
In: 00 · Habitação e estacionamento
Type - Material: Aço pintado / Stahl lackiert
Pset_CasaProvenance - DesignSource: Casa Sobreposta / configuration.json; ReferenceFile: 260617_CasaDFL_Estrutura_Terreno.ifc; ConstructionBasis: DESIGN_ASSUMPTION; Note: Reference section; spans, stability and connections require design.

# IfcBuildingElementProxy: Acesso · caixa de retenção de sedimentos (2)
In: Lares · Rua das Mercês · artigo 4771
PredefinedType: USERDEFINED; Material: Caleiras · betão
Pset_CasaProvenance - DesignSource: Casa Sobreposta / configuration.json; ReferenceFile: 260617_CasaDFL_Estrutura_Terreno.ifc; ConstructionBasis: DESIGN_ASSUMPTION

# IfcBuildingElementProxy: Acesso · dreno lateral raso · leito drenante (74)
In: Lares · Rua das Mercês · artigo 4771
PredefinedType: USERDEFINED; Material: Brita drenante
Pset_CasaProvenance - DesignSource: Casa Sobreposta / configuration.json; ReferenceFile: 260617_CasaDFL_Estrutura_Terreno.ifc; ConstructionBasis: DESIGN_ASSUMPTION; Note: R08 concept geometry; dimensions and connections not structurally verified.

# IfcBuildingElementProxy: Cisterna · água a 2,00 m, hipótese
In: -01 · Cisterna sob o terraço
PredefinedType: USERDEFINED; Material: Água pluvial · nível ilustrativo
Pset_CasaProvenance - DesignSource: Casa Sobreposta / configuration.json; ReferenceFile: 260617_CasaDFL_Estrutura_Terreno.ifc; ConstructionBasis: DESIGN_ASSUMPTION; Note: Illustrative water envelope, not concrete or a certified operating capacity.

# IfcBuildingElementProxy: Interceção · caleira estacionamento · leito drenante (8)
In: Lares · Rua das Mercês · artigo 4771
PredefinedType: USERDEFINED; Material: Brita drenante
Pset_CasaProvenance - DesignSource: Casa Sobreposta / configuration.json; ReferenceFile: 260617_CasaDFL_Estrutura_Terreno.ifc; ConstructionBasis: DESIGN_ASSUMPTION; Note: R08 concept geometry; dimensions and connections not structurally verified.

# IfcBuildingElementProxy: Interceção · caleira rua · leito drenante (8)
In: Lares · Rua das Mercês · artigo 4771
PredefinedType: USERDEFINED; Material: Brita drenante
Pset_CasaProvenance - DesignSource: Casa Sobreposta / configuration.json; ReferenceFile: 260617_CasaDFL_Estrutura_Terreno.ifc; ConstructionBasis: DESIGN_ASSUMPTION; Note: R08 concept geometry; dimensions and connections not structurally verified.

# IfcBuildingElementProxy: Limite north · gabião 10 · cesto galvanizado
In: Lares · Rua das Mercês · artigo 4771
PredefinedType: USERDEFINED; Material: Aço galvanizado / Stahl verzinkt
Pset_CasaProvenance - DesignSource: Casa Sobreposta / configuration.json; ReferenceFile: 260617_CasaDFL_Estrutura_Terreno.ifc; ConstructionBasis: DESIGN_ASSUMPTION; Note: R08 concept geometry; dimensions and connections not structurally verified.

# IfcBuildingElementProxy: Limite north · gabião 10 · pedra aparente
In: Lares · Rua das Mercês · artigo 4771
PredefinedType: USERDEFINED; Material: Gabião · pedra irregular
Pset_CasaProvenance - DesignSource: Casa Sobreposta / configuration.json; ReferenceFile: 260617_CasaDFL_Estrutura_Terreno.ifc; ConstructionBasis: DESIGN_ASSUMPTION; Note: R08 concept geometry; dimensions and connections not structurally verified.

# IfcBuildingElementProxy: Limite north · gabião 11 · cesto galvanizado
In: Lares · Rua das Mercês · artigo 4771
PredefinedType: USERDEFINED; Material: Aço galvanizado / Stahl verzinkt
Pset_CasaProvenance - DesignSource: Casa Sobreposta / configuration.json; ReferenceFile: 260617_CasaDFL_Estrutura_Terreno.ifc; ConstructionBasis: DESIGN_ASSUMPTION; Note: R08 concept geometry; dimensions and connections not structurally verified.

# IfcBuildingElementProxy: Limite north · gabião 11 · pedra aparente
In: Lares · Rua das Mercês · artigo 4771
PredefinedType: USERDEFINED; Material: Gabião · pedra irregular
Pset_CasaProvenance - DesignSource: Casa Sobreposta / configuration.json; ReferenceFile: 260617_CasaDFL_Estrutura_Terreno.ifc; ConstructionBasis: DESIGN_ASSUMPTION; Note: R08 concept geometry; dimensions and connections not structurally verified.

# IfcBuildingElementProxy: Limite north · gabião 12 · cesto galvanizado
In: Lares · Rua das Mercês · artigo 4771
PredefinedType: USERDEFINED; Material: Aço galvanizado / Stahl verzinkt
Pset_CasaProvenance - DesignSource: Casa Sobreposta / configuration.json; ReferenceFile: 260617_CasaDFL_Estrutura_Terreno.ifc; ConstructionBasis: DESIGN_ASSUMPTION; Note: R08 concept geometry; dimensions and connections not structurally verified.

# IfcBuildingElementProxy: Limite north · gabião 12 · pedra aparente
In: Lares · Rua das Mercês · artigo 4771
PredefinedType: USERDEFINED; Material: Gabião · pedra irregular
Pset_CasaProvenance - DesignSource: Casa Sobreposta / configuration.json; ReferenceFile: 260617_CasaDFL_Estrutura_Terreno.ifc; ConstructionBasis: DESIGN_ASSUMPTION; Note: R08 concept geometry; dimensions and connections not structurally verified.

# IfcBuildingElementProxy: Limite north · gabião 13 · cesto galvanizado
In: Lares · Rua das Mercês · artigo 4771
PredefinedType: USERDEFINED; Material: Aço galvanizado / Stahl verzinkt
Pset_CasaProvenance - DesignSource: Casa Sobreposta / configuration.json; ReferenceFile: 260617_CasaDFL_Estrutura_Terreno.ifc; ConstructionBasis: DESIGN_ASSUMPTION; Note: R08 concept geometry; dimensions and connections not structurally verified.

# IfcBuildingElementProxy: Limite north · gabião 13 · pedra aparente
In: Lares · Rua das Mercês · artigo 4771
PredefinedType: USERDEFINED; Material: Gabião · pedra irregular
Pset_CasaProvenance - DesignSource: Casa Sobreposta / configuration.json; ReferenceFile: 260617_CasaDFL_Estrutura_Terreno.ifc; ConstructionBasis: DESIGN_ASSUMPTION; Note: R08 concept geometry; dimensions and connections not structurally verified.

# IfcBuildingElementProxy: Limite north · gabião 14 · cesto galvanizado
In: Lares · Rua das Mercês · artigo 4771
PredefinedType: USERDEFINED; Material: Aço galvanizado / Stahl verzinkt
Pset_CasaProvenance - DesignSource: Casa Sobreposta / configuration.json; ReferenceFile: 260617_CasaDFL_Estrutura_Terreno.ifc; ConstructionBasis: DESIGN_ASSUMPTION; Note: R08 concept geometry; dimensions and connections not structurally verified.

# IfcBuildingElementProxy: Limite north · gabião 14 · pedra aparente
In: Lares · Rua das Mercês · artigo 4771
PredefinedType: USERDEFINED; Material: Gabião · pedra irregular
Pset_CasaProvenance - DesignSource: Casa Sobreposta / configuration.json; ReferenceFile: 260617_CasaDFL_Estrutura_Terreno.ifc; ConstructionBasis: DESIGN_ASSUMPTION; Note: R08 concept geometry; dimensions and connections not structurally verified.

# IfcBuildingElementProxy: Limite north · gabião 15 · cesto galvanizado
In: Lares · Rua das Mercês · artigo 4771
PredefinedType: USERDEFINED; Material: Aço galvanizado / Stahl verzinkt
Pset_CasaProvenance - DesignSource: Casa Sobreposta / configuration.json; ReferenceFile: 260617_CasaDFL_Estrutura_Terreno.ifc; ConstructionBasis: DESIGN_ASSUMPTION; Note: R08 concept geometry; dimensions and connections not structurally verified.

# IfcBuildingElementProxy: Limite north · gabião 15 · pedra aparente
In: Lares · Rua das Mercês · artigo 4771
PredefinedType: USERDEFINED; Material: Gabião · pedra irregular
Pset_CasaProvenance - DesignSource: Casa Sobreposta / configuration.json; ReferenceFile: 260617_CasaDFL_Estrutura_Terreno.ifc; ConstructionBasis: DESIGN_ASSUMPTION; Note: R08 concept geometry; dimensions and connections not structurally verified.

# IfcBuildingElementProxy: Limite north · gabião 16 · cesto galvanizado
In: Lares · Rua das Mercês · artigo 4771
PredefinedType: USERDEFINED; Material: Aço galvanizado / Stahl verzinkt
Pset_CasaProvenance - DesignSource: Casa Sobreposta / configuration.json; ReferenceFile: 260617_CasaDFL_Estrutura_Terreno.ifc; ConstructionBasis: DESIGN_ASSUMPTION; Note: R08 concept geometry; dimensions and connections not structurally verified.

# IfcBuildingElementProxy: Limite north · gabião 16 · pedra aparente
In: Lares · Rua das Mercês · artigo 4771
PredefinedType: USERDEFINED; Material: Gabião · pedra irregular
Pset_CasaProvenance - DesignSource: Casa Sobreposta / configuration.json; ReferenceFile: 260617_CasaDFL_Estrutura_Terreno.ifc; ConstructionBasis: DESIGN_ASSUMPTION; Note: R08 concept geometry; dimensions and connections not structurally verified.

# IfcBuildingElementProxy: Limite north · gabião 17 · cesto galvanizado
In: Lares · Rua das Mercês · artigo 4771
PredefinedType: USERDEFINED; Material: Aço galvanizado / Stahl verzinkt
Pset_CasaProvenance - DesignSource: Casa Sobreposta / configuration.json; ReferenceFile: 260617_CasaDFL_Estrutura_Terreno.ifc; ConstructionBasis: DESIGN_ASSUMPTION; Note: R08 concept geometry; dimensions and connections not structurally verified.

# IfcBuildingElementProxy: Limite north · gabião 17 · pedra aparente
In: Lares · Rua das Mercês · artigo 4771
PredefinedType: USERDEFINED; Material: Gabião · pedra irregular
Pset_CasaProvenance - DesignSource: Casa Sobreposta / configuration.json; ReferenceFile: 260617_CasaDFL_Estrutura_Terreno.ifc; ConstructionBasis: DESIGN_ASSUMPTION; Note: R08 concept geometry; dimensions and connections not structurally verified.

# IfcBuildingElementProxy: Limite north · gabião 18 · cesto galvanizado
In: Lares · Rua das Mercês · artigo 4771
PredefinedType: USERDEFINED; Material: Aço galvanizado / Stahl verzinkt
Pset_CasaProvenance - DesignSource: Casa Sobreposta / configuration.json; ReferenceFile: 260617_CasaDFL_Estrutura_Terreno.ifc; ConstructionBasis: DESIGN_ASSUMPTION; Note: R08 concept geometry; dimensions and connections not structurally verified.

# IfcBuildingElementProxy: Limite north · gabião 18 · pedra aparente
In: Lares · Rua das Mercês · artigo 4771
PredefinedType: USERDEFINED; Material: Gabião · pedra irregular
Pset_CasaProvenance - DesignSource: Casa Sobreposta / configuration.json; ReferenceFile: 260617_CasaDFL_Estrutura_Terreno.ifc; ConstructionBasis: DESIGN_ASSUMPTION; Note: R08 concept geometry; dimensions and connections not structurally verified.

# IfcBuildingElementProxy: Limite north · gabião 19 · cesto galvanizado
In: Lares · Rua das Mercês · artigo 4771
PredefinedType: USERDEFINED; Material: Aço galvanizado / Stahl verzinkt
Pset_CasaProvenance - DesignSource: Casa Sobreposta / configuration.json; ReferenceFile: 260617_CasaDFL_Estrutura_Terreno.ifc; ConstructionBasis: DESIGN_ASSUMPTION; Note: R08 concept geometry; dimensions and connections not structurally verified.

# IfcBuildingElementProxy: Limite north · gabião 19 · pedra aparente
In: Lares · Rua das Mercês · artigo 4771
PredefinedType: USERDEFINED; Material: Gabião · pedra irregular
Pset_CasaProvenance - DesignSource: Casa Sobreposta / configuration.json; ReferenceFile: 260617_CasaDFL_Estrutura_Terreno.ifc; ConstructionBasis: DESIGN_ASSUMPTION; Note: R08 concept geometry; dimensions and connections not structurally verified.

# IfcBuildingElementProxy: Limite north · gabião 20 · cesto galvanizado
In: Lares · Rua das Mercês · artigo 4771
PredefinedType: USERDEFINED; Material: Aço galvanizado / Stahl verzinkt
Pset_CasaProvenance - DesignSource: Casa Sobreposta / configuration.json; ReferenceFile: 260617_CasaDFL_Estrutura_Terreno.ifc; ConstructionBasis: DESIGN_ASSUMPTION; Note: R08 concept geometry; dimensions and connections not structurally verified.

# IfcBuildingElementProxy: Limite north · gabião 20 · pedra aparente
In: Lares · Rua das Mercês · artigo 4771
PredefinedType: USERDEFINED; Material: Gabião · pedra irregular
Pset_CasaProvenance - DesignSource: Casa Sobreposta / configuration.json; ReferenceFile: 260617_CasaDFL_Estrutura_Terreno.ifc; ConstructionBasis: DESIGN_ASSUMPTION; Note: R08 concept geometry; dimensions and connections not structurally verified.

# IfcBuildingElementProxy: Limite north · gabião 21 · cesto galvanizado
In: Lares · Rua das Mercês · artigo 4771
PredefinedType: USERDEFINED; Material: Aço galvanizado / Stahl verzinkt
Pset_CasaProvenance - DesignSource: Casa Sobreposta / configuration.json; ReferenceFile: 260617_CasaDFL_Estrutura_Terreno.ifc; ConstructionBasis: DESIGN_ASSUMPTION; Note: R08 concept geometry; dimensions and connections not structurally verified.

# IfcBuildingElementProxy: Limite north · gabião 21 · pedra aparente
In: Lares · Rua das Mercês · artigo 4771
PredefinedType: USERDEFINED; Material: Gabião · pedra irregular
Pset_CasaProvenance - DesignSource: Casa Sobreposta / configuration.json; ReferenceFile: 260617_CasaDFL_Estrutura_Terreno.ifc; ConstructionBasis: DESIGN_ASSUMPTION; Note: R08 concept geometry; dimensions and connections not structurally verified.

# IfcBuildingElementProxy: Limite north · gabião 22 · cesto galvanizado
In: Lares · Rua das Mercês · artigo 4771
PredefinedType: USERDEFINED; Material: Aço galvanizado / Stahl verzinkt
Pset_CasaProvenance - DesignSource: Casa Sobreposta / configuration.json; ReferenceFile: 260617_CasaDFL_Estrutura_Terreno.ifc; ConstructionBasis: DESIGN_ASSUMPTION; Note: R08 concept geometry; dimensions and connections not structurally verified.

# IfcBuildingElementProxy: Limite north · gabião 22 · pedra aparente
In: Lares · Rua das Mercês · artigo 4771
PredefinedType: USERDEFINED; Material: Gabião · pedra irregular
Pset_CasaProvenance - DesignSource: Casa Sobreposta / configuration.json; ReferenceFile: 260617_CasaDFL_Estrutura_Terreno.ifc; ConstructionBasis: DESIGN_ASSUMPTION; Note: R08 concept geometry; dimensions and connections not structurally verified.

# IfcBuildingElementProxy: Limite north · gabião 23 · cesto galvanizado
In: Lares · Rua das Mercês · artigo 4771
PredefinedType: USERDEFINED; Material: Aço galvanizado / Stahl verzinkt
Pset_CasaProvenance - DesignSource: Casa Sobreposta / configuration.json; ReferenceFile: 260617_CasaDFL_Estrutura_Terreno.ifc; ConstructionBasis: DESIGN_ASSUMPTION; Note: R08 concept geometry; dimensions and connections not structurally verified.

# IfcBuildingElementProxy: Limite north · gabião 23 · pedra aparente
In: Lares · Rua das Mercês · artigo 4771
PredefinedType: USERDEFINED; Material: Gabião · pedra irregular
Pset_CasaProvenance - DesignSource: Casa Sobreposta / configuration.json; ReferenceFile: 260617_CasaDFL_Estrutura_Terreno.ifc; ConstructionBasis: DESIGN_ASSUMPTION; Note: R08 concept geometry; dimensions and connections not structurally verified.

# IfcBuildingElementProxy: Limite north · gabião 24 · cesto galvanizado
In: Lares · Rua das Mercês · artigo 4771
PredefinedType: USERDEFINED; Material: Aço galvanizado / Stahl verzinkt
Pset_CasaProvenance - DesignSource: Casa Sobreposta / configuration.json; ReferenceFile: 260617_CasaDFL_Estrutura_Terreno.ifc; ConstructionBasis: DESIGN_ASSUMPTION; Note: R08 concept geometry; dimensions and connections not structurally verified.

# IfcBuildingElementProxy: Limite north · gabião 24 · pedra aparente
In: Lares · Rua das Mercês · artigo 4771
PredefinedType: USERDEFINED; Material: Gabião · pedra irregular
Pset_CasaProvenance - DesignSource: Casa Sobreposta / configuration.json; ReferenceFile: 260617_CasaDFL_Estrutura_Terreno.ifc; ConstructionBasis: DESIGN_ASSUMPTION; Note: R08 concept geometry; dimensions and connections not structurally verified.

# IfcBuildingElementProxy: Limite north · gabião 25 · cesto galvanizado
In: Lares · Rua das Mercês · artigo 4771
PredefinedType: USERDEFINED; Material: Aço galvanizado / Stahl verzinkt
Pset_CasaProvenance - DesignSource: Casa Sobreposta / configuration.json; ReferenceFile: 260617_CasaDFL_Estrutura_Terreno.ifc; ConstructionBasis: DESIGN_ASSUMPTION; Note: R08 concept geometry; dimensions and connections not structurally verified.

# IfcBuildingElementProxy: Limite north · gabião 25 · pedra aparente
In: Lares · Rua das Mercês · artigo 4771
PredefinedType: USERDEFINED; Material: Gabião · pedra irregular
Pset_CasaProvenance - DesignSource: Casa Sobreposta / configuration.json; ReferenceFile: 260617_CasaDFL_Estrutura_Terreno.ifc; ConstructionBasis: DESIGN_ASSUMPTION; Note: R08 concept geometry; dimensions and connections not structurally verified.

# IfcBuildingElementProxy: Limite north · gabião 26 · cesto galvanizado
In: Lares · Rua das Mercês · artigo 4771
PredefinedType: USERDEFINED; Material: Aço galvanizado / Stahl verzinkt
Pset_CasaProvenance - DesignSource: Casa Sobreposta / configuration.json; ReferenceFile: 260617_CasaDFL_Estrutura_Terreno.ifc; ConstructionBasis: DESIGN_ASSUMPTION; Note: R08 concept geometry; dimensions and connections not structurally verified.

# IfcBuildingElementProxy: Limite north · gabião 26 · pedra aparente
In: Lares · Rua das Mercês · artigo 4771
PredefinedType: USERDEFINED; Material: Gabião · pedra irregular
Pset_CasaProvenance - DesignSource: Casa Sobreposta / configuration.json; ReferenceFile: 260617_CasaDFL_Estrutura_Terreno.ifc; ConstructionBasis: DESIGN_ASSUMPTION; Note: R08 concept geometry; dimensions and connections not structurally verified.

# IfcBuildingElementProxy: Limite north · gabião 27 · cesto galvanizado
In: Lares · Rua das Mercês · artigo 4771
PredefinedType: USERDEFINED; Material: Aço galvanizado / Stahl verzinkt
Pset_CasaProvenance - DesignSource: Casa Sobreposta / configuration.json; ReferenceFile: 260617_CasaDFL_Estrutura_Terreno.ifc; ConstructionBasis: DESIGN_ASSUMPTION; Note: R08 concept geometry; dimensions and connections not structurally verified.

# IfcBuildingElementProxy: Limite north · gabião 27 · pedra aparente
In: Lares · Rua das Mercês · artigo 4771
PredefinedType: USERDEFINED; Material: Gabião · pedra irregular
Pset_CasaProvenance - DesignSource: Casa Sobreposta / configuration.json; ReferenceFile: 260617_CasaDFL_Estrutura_Terreno.ifc; ConstructionBasis: DESIGN_ASSUMPTION; Note: R08 concept geometry; dimensions and connections not structurally verified.

# IfcBuildingElementProxy: Limite north · gabião 4 · cesto galvanizado
In: Lares · Rua das Mercês · artigo 4771
PredefinedType: USERDEFINED; Material: Aço galvanizado / Stahl verzinkt
Pset_CasaProvenance - DesignSource: Casa Sobreposta / configuration.json; ReferenceFile: 260617_CasaDFL_Estrutura_Terreno.ifc; ConstructionBasis: DESIGN_ASSUMPTION; Note: R08 concept geometry; dimensions and connections not structurally verified.

# IfcBuildingElementProxy: Limite north · gabião 4 · pedra aparente
In: Lares · Rua das Mercês · artigo 4771
PredefinedType: USERDEFINED; Material: Gabião · pedra irregular
Pset_CasaProvenance - DesignSource: Casa Sobreposta / configuration.json; ReferenceFile: 260617_CasaDFL_Estrutura_Terreno.ifc; ConstructionBasis: DESIGN_ASSUMPTION; Note: R08 concept geometry; dimensions and connections not structurally verified.

# IfcBuildingElementProxy: Limite north · gabião 5 · cesto galvanizado
In: Lares · Rua das Mercês · artigo 4771
PredefinedType: USERDEFINED; Material: Aço galvanizado / Stahl verzinkt
Pset_CasaProvenance - DesignSource: Casa Sobreposta / configuration.json; ReferenceFile: 260617_CasaDFL_Estrutura_Terreno.ifc; ConstructionBasis: DESIGN_ASSUMPTION; Note: R08 concept geometry; dimensions and connections not structurally verified.

# IfcBuildingElementProxy: Limite north · gabião 5 · pedra aparente
In: Lares · Rua das Mercês · artigo 4771
PredefinedType: USERDEFINED; Material: Gabião · pedra irregular
Pset_CasaProvenance - DesignSource: Casa Sobreposta / configuration.json; ReferenceFile: 260617_CasaDFL_Estrutura_Terreno.ifc; ConstructionBasis: DESIGN_ASSUMPTION; Note: R08 concept geometry; dimensions and connections not structurally verified.

# IfcBuildingElementProxy: Limite north · gabião 6 · cesto galvanizado
In: Lares · Rua das Mercês · artigo 4771
PredefinedType: USERDEFINED; Material: Aço galvanizado / Stahl verzinkt
Pset_CasaProvenance - DesignSource: Casa Sobreposta / configuration.json; ReferenceFile: 260617_CasaDFL_Estrutura_Terreno.ifc; ConstructionBasis: DESIGN_ASSUMPTION; Note: R08 concept geometry; dimensions and connections not structurally verified.

# IfcBuildingElementProxy: Limite north · gabião 6 · pedra aparente
In: Lares · Rua das Mercês · artigo 4771
PredefinedType: USERDEFINED; Material: Gabião · pedra irregular
Pset_CasaProvenance - DesignSource: Casa Sobreposta / configuration.json; ReferenceFile: 260617_CasaDFL_Estrutura_Terreno.ifc; ConstructionBasis: DESIGN_ASSUMPTION; Note: R08 concept geometry; dimensions and connections not structurally verified.

# IfcBuildingElementProxy: Limite north · gabião 7 · cesto galvanizado
In: Lares · Rua das Mercês · artigo 4771
PredefinedType: USERDEFINED; Material: Aço galvanizado / Stahl verzinkt
Pset_CasaProvenance - DesignSource: Casa Sobreposta / configuration.json; ReferenceFile: 260617_CasaDFL_Estrutura_Terreno.ifc; ConstructionBasis: DESIGN_ASSUMPTION; Note: R08 concept geometry; dimensions and connections not structurally verified.

# IfcBuildingElementProxy: Limite north · gabião 7 · pedra aparente
In: Lares · Rua das Mercês · artigo 4771
PredefinedType: USERDEFINED; Material: Gabião · pedra irregular
Pset_CasaProvenance - DesignSource: Casa Sobreposta / configuration.json; ReferenceFile: 260617_CasaDFL_Estrutura_Terreno.ifc; ConstructionBasis: DESIGN_ASSUMPTION; Note: R08 concept geometry; dimensions and connections not structurally verified.

# IfcBuildingElementProxy: Limite north · gabião 8 · cesto galvanizado
In: Lares · Rua das Mercês · artigo 4771
PredefinedType: USERDEFINED; Material: Aço galvanizado / Stahl verzinkt
Pset_CasaProvenance - DesignSource: Casa Sobreposta / configuration.json; ReferenceFile: 260617_CasaDFL_Estrutura_Terreno.ifc; ConstructionBasis: DESIGN_ASSUMPTION; Note: R08 concept geometry; dimensions and connections not structurally verified.

# IfcBuildingElementProxy: Limite north · gabião 8 · pedra aparente
In: Lares · Rua das Mercês · artigo 4771
PredefinedType: USERDEFINED; Material: Gabião · pedra irregular
Pset_CasaProvenance - DesignSource: Casa Sobreposta / configuration.json; ReferenceFile: 260617_CasaDFL_Estrutura_Terreno.ifc; ConstructionBasis: DESIGN_ASSUMPTION; Note: R08 concept geometry; dimensions and connections not structurally verified.

# IfcBuildingElementProxy: Limite north · gabião 9 · cesto galvanizado
In: Lares · Rua das Mercês · artigo 4771
PredefinedType: USERDEFINED; Material: Aço galvanizado / Stahl verzinkt
Pset_CasaProvenance - DesignSource: Casa Sobreposta / configuration.json; ReferenceFile: 260617_CasaDFL_Estrutura_Terreno.ifc; ConstructionBasis: DESIGN_ASSUMPTION; Note: R08 concept geometry; dimensions and connections not structurally verified.

# IfcBuildingElementProxy: Limite north · gabião 9 · pedra aparente
In: Lares · Rua das Mercês · artigo 4771
PredefinedType: USERDEFINED; Material: Gabião · pedra irregular
Pset_CasaProvenance - DesignSource: Casa Sobreposta / configuration.json; ReferenceFile: 260617_CasaDFL_Estrutura_Terreno.ifc; ConstructionBasis: DESIGN_ASSUMPTION; Note: R08 concept geometry; dimensions and connections not structurally verified.

# IfcBuildingElementProxy: Limite north · vala de interceção (37)
In: Lares · Rua das Mercês · artigo 4771
PredefinedType: USERDEFINED; Material: Brita drenante
Pset_CasaProvenance - DesignSource: Casa Sobreposta / configuration.json; ReferenceFile: 260617_CasaDFL_Estrutura_Terreno.ifc; ConstructionBasis: DESIGN_ASSUMPTION

# IfcBuildingElementProxy: Limite south · gabião 1 · cesto galvanizado
In: Lares · Rua das Mercês · artigo 4771
PredefinedType: USERDEFINED; Material: Aço galvanizado / Stahl verzinkt
Pset_CasaProvenance - DesignSource: Casa Sobreposta / configuration.json; ReferenceFile: 260617_CasaDFL_Estrutura_Terreno.ifc; ConstructionBasis: DESIGN_ASSUMPTION; Note: R08 concept geometry; dimensions and connections not structurally verified.

# IfcBuildingElementProxy: Limite south · gabião 1 · pedra aparente
In: Lares · Rua das Mercês · artigo 4771
PredefinedType: USERDEFINED; Material: Gabião · pedra irregular
Pset_CasaProvenance - DesignSource: Casa Sobreposta / configuration.json; ReferenceFile: 260617_CasaDFL_Estrutura_Terreno.ifc; ConstructionBasis: DESIGN_ASSUMPTION; Note: R08 concept geometry; dimensions and connections not structurally verified.

# IfcBuildingElementProxy: Limite south · gabião 10 · cesto galvanizado
In: Lares · Rua das Mercês · artigo 4771
PredefinedType: USERDEFINED; Material: Aço galvanizado / Stahl verzinkt
Pset_CasaProvenance - DesignSource: Casa Sobreposta / configuration.json; ReferenceFile: 260617_CasaDFL_Estrutura_Terreno.ifc; ConstructionBasis: DESIGN_ASSUMPTION; Note: R08 concept geometry; dimensions and connections not structurally verified.

# IfcBuildingElementProxy: Limite south · gabião 10 · pedra aparente
In: Lares · Rua das Mercês · artigo 4771
PredefinedType: USERDEFINED; Material: Gabião · pedra irregular
Pset_CasaProvenance - DesignSource: Casa Sobreposta / configuration.json; ReferenceFile: 260617_CasaDFL_Estrutura_Terreno.ifc; ConstructionBasis: DESIGN_ASSUMPTION; Note: R08 concept geometry; dimensions and connections not structurally verified.

# IfcBuildingElementProxy: Limite south · gabião 11 · cesto galvanizado
In: Lares · Rua das Mercês · artigo 4771
PredefinedType: USERDEFINED; Material: Aço galvanizado / Stahl verzinkt
Pset_CasaProvenance - DesignSource: Casa Sobreposta / configuration.json; ReferenceFile: 260617_CasaDFL_Estrutura_Terreno.ifc; ConstructionBasis: DESIGN_ASSUMPTION; Note: R08 concept geometry; dimensions and connections not structurally verified.

# IfcBuildingElementProxy: Limite south · gabião 11 · pedra aparente
In: Lares · Rua das Mercês · artigo 4771
PredefinedType: USERDEFINED; Material: Gabião · pedra irregular
Pset_CasaProvenance - DesignSource: Casa Sobreposta / configuration.json; ReferenceFile: 260617_CasaDFL_Estrutura_Terreno.ifc; ConstructionBasis: DESIGN_ASSUMPTION; Note: R08 concept geometry; dimensions and connections not structurally verified.

# IfcBuildingElementProxy: Limite south · gabião 12 · cesto galvanizado
In: Lares · Rua das Mercês · artigo 4771
PredefinedType: USERDEFINED; Material: Aço galvanizado / Stahl verzinkt
Pset_CasaProvenance - DesignSource: Casa Sobreposta / configuration.json; ReferenceFile: 260617_CasaDFL_Estrutura_Terreno.ifc; ConstructionBasis: DESIGN_ASSUMPTION; Note: R08 concept geometry; dimensions and connections not structurally verified.

# IfcBuildingElementProxy: Limite south · gabião 12 · pedra aparente
In: Lares · Rua das Mercês · artigo 4771
PredefinedType: USERDEFINED; Material: Gabião · pedra irregular
Pset_CasaProvenance - DesignSource: Casa Sobreposta / configuration.json; ReferenceFile: 260617_CasaDFL_Estrutura_Terreno.ifc; ConstructionBasis: DESIGN_ASSUMPTION; Note: R08 concept geometry; dimensions and connections not structurally verified.

# IfcBuildingElementProxy: Limite south · gabião 13 · cesto galvanizado
In: Lares · Rua das Mercês · artigo 4771
PredefinedType: USERDEFINED; Material: Aço galvanizado / Stahl verzinkt
